One B-rep face of a CAD part: STEP entity #558.
In plain terms, the planar face has unit normal (1, 0, 0).
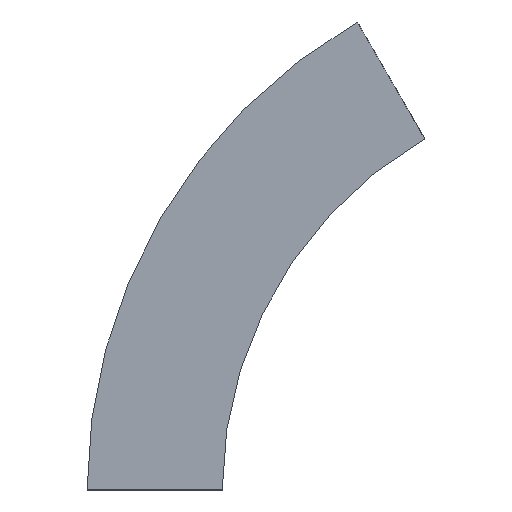
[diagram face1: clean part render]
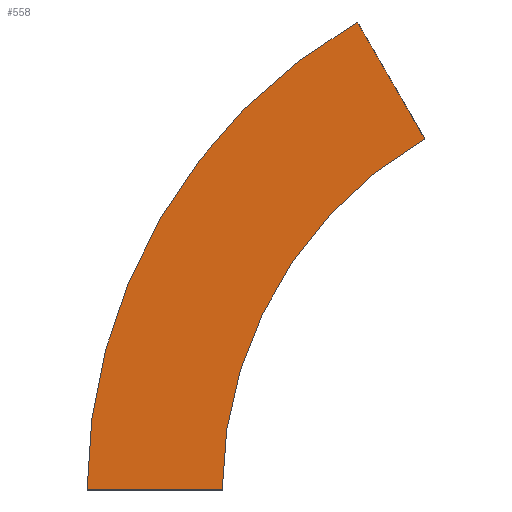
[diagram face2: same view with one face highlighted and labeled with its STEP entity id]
Its self-contained STEP definition (entity closure, numbers rounded to 3 decimals):
#5 = CARTESIAN_POINT ( 'NONE',  ( 0., -300., 0. ) ) ;
#28 = CARTESIAN_POINT ( 'NONE',  ( 0., 0., 0. ) ) ;
#53 = CARTESIAN_POINT ( 'NONE',  ( 0., 0., 0. ) ) ;
#81 = LINE ( 'NONE', #210, #493 ) ;
#169 = DIRECTION ( 'NONE',  ( 0., 1., 0. ) ) ;
#182 = CARTESIAN_POINT ( 'NONE',  ( 0., -150., 259.808 ) ) ;
#185 = VERTEX_POINT ( 'NONE', #28 ) ;
#195 = ORIENTED_EDGE ( 'NONE', *, *, #335, .T. ) ;
#199 = CIRCLE ( 'NONE', #529, 300. ) ;
#210 = CARTESIAN_POINT ( 'NONE',  ( 0., 0., 0. ) ) ;
#261 = CARTESIAN_POINT ( 'NONE',  ( 0., -300., 0. ) ) ;
#265 = VERTEX_POINT ( 'NONE', #384 ) ;
#268 = VECTOR ( 'NONE', #548, 1000. ) ;
#274 = DIRECTION ( 'NONE',  ( 1., 0., 0. ) ) ;
#299 = DIRECTION ( 'NONE',  ( 0., 1., 0. ) ) ;
#301 = EDGE_CURVE ( 'NONE', #185, #265, #81, .T. ) ;
#320 = VERTEX_POINT ( 'NONE', #496 ) ;
#325 = CARTESIAN_POINT ( 'NONE',  ( 0., -150., 259.808 ) ) ;
#335 = EDGE_CURVE ( 'NONE', #265, #320, #396, .T. ) ;
#343 = ORIENTED_EDGE ( 'NONE', *, *, #301, .T. ) ;
#349 = DIRECTION ( 'NONE',  ( 1., 0., 0. ) ) ;
#351 = VERTEX_POINT ( 'NONE', #182 ) ;
#372 = LINE ( 'NONE', #325, #268 ) ;
#384 = CARTESIAN_POINT ( 'NONE',  ( 0., 100., 0. ) ) ;
#396 = CIRCLE ( 'NONE', #448, 400. ) ;
#400 = PLANE ( 'NONE',  #518 ) ;
#404 = DIRECTION ( 'NONE',  ( 0., 0., -1. ) ) ;
#427 = EDGE_CURVE ( 'NONE', #351, #320, #372, .T. ) ;
#448 = AXIS2_PLACEMENT_3D ( 'NONE', #5, #274, #541 ) ;
#453 = FACE_OUTER_BOUND ( 'NONE', #455, .T. ) ;
#455 = EDGE_LOOP ( 'NONE', ( #195, #489, #525, #343 ) ) ;
#489 = ORIENTED_EDGE ( 'NONE', *, *, #427, .F. ) ;
#493 = VECTOR ( 'NONE', #169, 1000. ) ;
#496 = CARTESIAN_POINT ( 'NONE',  ( 0., -100., 346.41 ) ) ;
#497 = EDGE_CURVE ( 'NONE', #185, #351, #199, .T. ) ;
#518 = AXIS2_PLACEMENT_3D ( 'NONE', #53, #543, #404 ) ;
#525 = ORIENTED_EDGE ( 'NONE', *, *, #497, .F. ) ;
#529 = AXIS2_PLACEMENT_3D ( 'NONE', #261, #349, #299 ) ;
#541 = DIRECTION ( 'NONE',  ( 0., 1., 0. ) ) ;
#543 = DIRECTION ( 'NONE',  ( 1., 0., 0. ) ) ;
#548 = DIRECTION ( 'NONE',  ( 0., 0.5, 0.866 ) ) ;
#558 = ADVANCED_FACE ( 'NONE', ( #453 ), #400, .T. ) ;
